VERSION 5.8 ;
BUSBITCHARS "[]" ;
DIVIDERCHAR "/" ;
UNITS
    DATABASE MICRONS 1000 ;
END UNITS

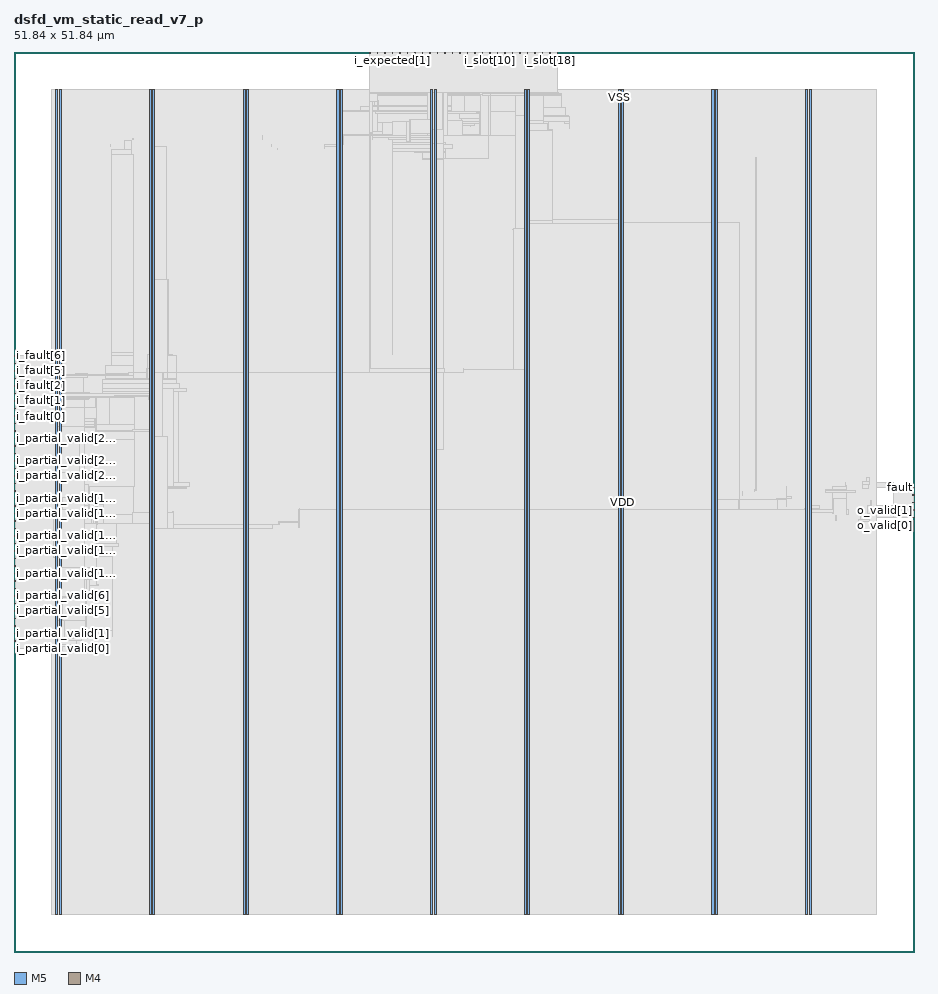
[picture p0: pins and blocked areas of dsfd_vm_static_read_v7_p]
MACRO dsfd_vm_static_read_v7_p
  FOREIGN dsfd_vm_static_read_v7_p 0 0 ;
  CLASS BLOCK ;
  SIZE 51.84 BY 51.84 ;
  PIN ck
    DIRECTION INPUT ;
    USE SIGNAL ;
    PORT
      LAYER M5 ;
        RECT  20.496 51.756 20.52 51.84 ;
    END
  END ck
  PIN fault
    DIRECTION OUTPUT ;
    USE SIGNAL ;
    PORT
      LAYER M4 ;
        RECT  51.756 26.736 51.84 26.76 ;
    END
  END fault
  PIN i_expected[0]
    DIRECTION INPUT ;
    USE SIGNAL ;
    PORT
      LAYER M5 ;
        RECT  21.36 51.756 21.384 51.84 ;
    END
  END i_expected[0]
  PIN i_expected[1]
    DIRECTION INPUT ;
    USE SIGNAL ;
    PORT
      LAYER M5 ;
        RECT  21.792 51.756 21.816 51.84 ;
    END
  END i_expected[1]
  PIN i_expected[2]
    DIRECTION INPUT ;
    USE SIGNAL ;
    PORT
      LAYER M5 ;
        RECT  22.224 51.756 22.248 51.84 ;
    END
  END i_expected[2]
  PIN i_expected[3]
    DIRECTION INPUT ;
    USE SIGNAL ;
    PORT
      LAYER M5 ;
        RECT  22.656 51.756 22.68 51.84 ;
    END
  END i_expected[3]
  PIN i_fault[0]
    DIRECTION INPUT ;
    USE SIGNAL ;
    PORT
      LAYER M4 ;
        RECT  0 31.296 0.084 31.32 ;
    END
  END i_fault[0]
  PIN i_fault[1]
    DIRECTION INPUT ;
    USE SIGNAL ;
    PORT
      LAYER M4 ;
        RECT  0 31.728 0.084 31.752 ;
    END
  END i_fault[1]
  PIN i_fault[2]
    DIRECTION INPUT ;
    USE SIGNAL ;
    PORT
      LAYER M4 ;
        RECT  0 32.16 0.084 32.184 ;
    END
  END i_fault[2]
  PIN i_fault[3]
    DIRECTION INPUT ;
    USE SIGNAL ;
    PORT
      LAYER M4 ;
        RECT  0 32.592 0.084 32.616 ;
    END
  END i_fault[3]
  PIN i_fault[4]
    DIRECTION INPUT ;
    USE SIGNAL ;
    PORT
      LAYER M4 ;
        RECT  0 33.024 0.084 33.048 ;
    END
  END i_fault[4]
  PIN i_fault[5]
    DIRECTION INPUT ;
    USE SIGNAL ;
    PORT
      LAYER M4 ;
        RECT  0 33.456 0.084 33.48 ;
    END
  END i_fault[5]
  PIN i_fault[6]
    DIRECTION INPUT ;
    USE SIGNAL ;
    PORT
      LAYER M4 ;
        RECT  0 33.888 0.084 33.912 ;
    END
  END i_fault[6]
  PIN i_fault[7]
    DIRECTION INPUT ;
    USE SIGNAL ;
    PORT
      LAYER M4 ;
        RECT  0 34.32 0.084 34.344 ;
    END
  END i_fault[7]
  PIN i_partial_valid[0]
    DIRECTION INPUT ;
    USE SIGNAL ;
    PORT
      LAYER M4 ;
        RECT  0 17.472 0.084 17.496 ;
    END
  END i_partial_valid[0]
  PIN i_partial_valid[10]
    DIRECTION INPUT ;
    USE SIGNAL ;
    PORT
      LAYER M4 ;
        RECT  0 21.792 0.084 21.816 ;
    END
  END i_partial_valid[10]
  PIN i_partial_valid[11]
    DIRECTION INPUT ;
    USE SIGNAL ;
    PORT
      LAYER M4 ;
        RECT  0 22.224 0.084 22.248 ;
    END
  END i_partial_valid[11]
  PIN i_partial_valid[12]
    DIRECTION INPUT ;
    USE SIGNAL ;
    PORT
      LAYER M4 ;
        RECT  0 22.656 0.084 22.68 ;
    END
  END i_partial_valid[12]
  PIN i_partial_valid[13]
    DIRECTION INPUT ;
    USE SIGNAL ;
    PORT
      LAYER M4 ;
        RECT  0 23.088 0.084 23.112 ;
    END
  END i_partial_valid[13]
  PIN i_partial_valid[14]
    DIRECTION INPUT ;
    USE SIGNAL ;
    PORT
      LAYER M4 ;
        RECT  0 23.52 0.084 23.544 ;
    END
  END i_partial_valid[14]
  PIN i_partial_valid[15]
    DIRECTION INPUT ;
    USE SIGNAL ;
    PORT
      LAYER M4 ;
        RECT  0 23.952 0.084 23.976 ;
    END
  END i_partial_valid[15]
  PIN i_partial_valid[16]
    DIRECTION INPUT ;
    USE SIGNAL ;
    PORT
      LAYER M4 ;
        RECT  0 24.384 0.084 24.408 ;
    END
  END i_partial_valid[16]
  PIN i_partial_valid[17]
    DIRECTION INPUT ;
    USE SIGNAL ;
    PORT
      LAYER M4 ;
        RECT  0 24.816 0.084 24.84 ;
    END
  END i_partial_valid[17]
  PIN i_partial_valid[18]
    DIRECTION INPUT ;
    USE SIGNAL ;
    PORT
      LAYER M4 ;
        RECT  0 25.248 0.084 25.272 ;
    END
  END i_partial_valid[18]
  PIN i_partial_valid[19]
    DIRECTION INPUT ;
    USE SIGNAL ;
    PORT
      LAYER M4 ;
        RECT  0 25.68 0.084 25.704 ;
    END
  END i_partial_valid[19]
  PIN i_partial_valid[1]
    DIRECTION INPUT ;
    USE SIGNAL ;
    PORT
      LAYER M4 ;
        RECT  0 17.904 0.084 17.928 ;
    END
  END i_partial_valid[1]
  PIN i_partial_valid[20]
    DIRECTION INPUT ;
    USE SIGNAL ;
    PORT
      LAYER M4 ;
        RECT  0 26.112 0.084 26.136 ;
    END
  END i_partial_valid[20]
  PIN i_partial_valid[21]
    DIRECTION INPUT ;
    USE SIGNAL ;
    PORT
      LAYER M4 ;
        RECT  0 26.544 0.084 26.568 ;
    END
  END i_partial_valid[21]
  PIN i_partial_valid[22]
    DIRECTION INPUT ;
    USE SIGNAL ;
    PORT
      LAYER M4 ;
        RECT  0 26.976 0.084 27 ;
    END
  END i_partial_valid[22]
  PIN i_partial_valid[23]
    DIRECTION INPUT ;
    USE SIGNAL ;
    PORT
      LAYER M4 ;
        RECT  0 27.408 0.084 27.432 ;
    END
  END i_partial_valid[23]
  PIN i_partial_valid[24]
    DIRECTION INPUT ;
    USE SIGNAL ;
    PORT
      LAYER M4 ;
        RECT  0 27.84 0.084 27.864 ;
    END
  END i_partial_valid[24]
  PIN i_partial_valid[25]
    DIRECTION INPUT ;
    USE SIGNAL ;
    PORT
      LAYER M4 ;
        RECT  0 28.272 0.084 28.296 ;
    END
  END i_partial_valid[25]
  PIN i_partial_valid[26]
    DIRECTION INPUT ;
    USE SIGNAL ;
    PORT
      LAYER M4 ;
        RECT  0 28.704 0.084 28.728 ;
    END
  END i_partial_valid[26]
  PIN i_partial_valid[27]
    DIRECTION INPUT ;
    USE SIGNAL ;
    PORT
      LAYER M4 ;
        RECT  0 29.136 0.084 29.16 ;
    END
  END i_partial_valid[27]
  PIN i_partial_valid[28]
    DIRECTION INPUT ;
    USE SIGNAL ;
    PORT
      LAYER M4 ;
        RECT  0 29.568 0.084 29.592 ;
    END
  END i_partial_valid[28]
  PIN i_partial_valid[29]
    DIRECTION INPUT ;
    USE SIGNAL ;
    PORT
      LAYER M4 ;
        RECT  0 30 0.084 30.024 ;
    END
  END i_partial_valid[29]
  PIN i_partial_valid[2]
    DIRECTION INPUT ;
    USE SIGNAL ;
    PORT
      LAYER M4 ;
        RECT  0 18.336 0.084 18.36 ;
    END
  END i_partial_valid[2]
  PIN i_partial_valid[30]
    DIRECTION INPUT ;
    USE SIGNAL ;
    PORT
      LAYER M4 ;
        RECT  0 30.432 0.084 30.456 ;
    END
  END i_partial_valid[30]
  PIN i_partial_valid[31]
    DIRECTION INPUT ;
    USE SIGNAL ;
    PORT
      LAYER M4 ;
        RECT  0 30.864 0.084 30.888 ;
    END
  END i_partial_valid[31]
  PIN i_partial_valid[3]
    DIRECTION INPUT ;
    USE SIGNAL ;
    PORT
      LAYER M4 ;
        RECT  0 18.768 0.084 18.792 ;
    END
  END i_partial_valid[3]
  PIN i_partial_valid[4]
    DIRECTION INPUT ;
    USE SIGNAL ;
    PORT
      LAYER M4 ;
        RECT  0 19.2 0.084 19.224 ;
    END
  END i_partial_valid[4]
  PIN i_partial_valid[5]
    DIRECTION INPUT ;
    USE SIGNAL ;
    PORT
      LAYER M4 ;
        RECT  0 19.632 0.084 19.656 ;
    END
  END i_partial_valid[5]
  PIN i_partial_valid[6]
    DIRECTION INPUT ;
    USE SIGNAL ;
    PORT
      LAYER M4 ;
        RECT  0 20.064 0.084 20.088 ;
    END
  END i_partial_valid[6]
  PIN i_partial_valid[7]
    DIRECTION INPUT ;
    USE SIGNAL ;
    PORT
      LAYER M4 ;
        RECT  0 20.496 0.084 20.52 ;
    END
  END i_partial_valid[7]
  PIN i_partial_valid[8]
    DIRECTION INPUT ;
    USE SIGNAL ;
    PORT
      LAYER M4 ;
        RECT  0 20.928 0.084 20.952 ;
    END
  END i_partial_valid[8]
  PIN i_partial_valid[9]
    DIRECTION INPUT ;
    USE SIGNAL ;
    PORT
      LAYER M4 ;
        RECT  0 21.36 0.084 21.384 ;
    END
  END i_partial_valid[9]
  PIN i_slot[0]
    DIRECTION INPUT ;
    USE SIGNAL ;
    PORT
      LAYER M5 ;
        RECT  23.088 51.756 23.112 51.84 ;
    END
  END i_slot[0]
  PIN i_slot[10]
    DIRECTION INPUT ;
    USE SIGNAL ;
    PORT
      LAYER M5 ;
        RECT  27.408 51.756 27.432 51.84 ;
    END
  END i_slot[10]
  PIN i_slot[11]
    DIRECTION INPUT ;
    USE SIGNAL ;
    PORT
      LAYER M5 ;
        RECT  27.84 51.756 27.864 51.84 ;
    END
  END i_slot[11]
  PIN i_slot[12]
    DIRECTION INPUT ;
    USE SIGNAL ;
    PORT
      LAYER M5 ;
        RECT  28.272 51.756 28.296 51.84 ;
    END
  END i_slot[12]
  PIN i_slot[13]
    DIRECTION INPUT ;
    USE SIGNAL ;
    PORT
      LAYER M5 ;
        RECT  28.704 51.756 28.728 51.84 ;
    END
  END i_slot[13]
  PIN i_slot[14]
    DIRECTION INPUT ;
    USE SIGNAL ;
    PORT
      LAYER M5 ;
        RECT  29.136 51.756 29.16 51.84 ;
    END
  END i_slot[14]
  PIN i_slot[15]
    DIRECTION INPUT ;
    USE SIGNAL ;
    PORT
      LAYER M5 ;
        RECT  29.568 51.756 29.592 51.84 ;
    END
  END i_slot[15]
  PIN i_slot[16]
    DIRECTION INPUT ;
    USE SIGNAL ;
    PORT
      LAYER M5 ;
        RECT  30 51.756 30.024 51.84 ;
    END
  END i_slot[16]
  PIN i_slot[17]
    DIRECTION INPUT ;
    USE SIGNAL ;
    PORT
      LAYER M5 ;
        RECT  30.432 51.756 30.456 51.84 ;
    END
  END i_slot[17]
  PIN i_slot[18]
    DIRECTION INPUT ;
    USE SIGNAL ;
    PORT
      LAYER M5 ;
        RECT  30.864 51.756 30.888 51.84 ;
    END
  END i_slot[18]
  PIN i_slot[19]
    DIRECTION INPUT ;
    USE SIGNAL ;
    PORT
      LAYER M5 ;
        RECT  31.296 51.756 31.32 51.84 ;
    END
  END i_slot[19]
  PIN i_slot[1]
    DIRECTION INPUT ;
    USE SIGNAL ;
    PORT
      LAYER M5 ;
        RECT  23.52 51.756 23.544 51.84 ;
    END
  END i_slot[1]
  PIN i_slot[2]
    DIRECTION INPUT ;
    USE SIGNAL ;
    PORT
      LAYER M5 ;
        RECT  23.952 51.756 23.976 51.84 ;
    END
  END i_slot[2]
  PIN i_slot[3]
    DIRECTION INPUT ;
    USE SIGNAL ;
    PORT
      LAYER M5 ;
        RECT  24.384 51.756 24.408 51.84 ;
    END
  END i_slot[3]
  PIN i_slot[4]
    DIRECTION INPUT ;
    USE SIGNAL ;
    PORT
      LAYER M5 ;
        RECT  24.816 51.756 24.84 51.84 ;
    END
  END i_slot[4]
  PIN i_slot[5]
    DIRECTION INPUT ;
    USE SIGNAL ;
    PORT
      LAYER M5 ;
        RECT  25.248 51.756 25.272 51.84 ;
    END
  END i_slot[5]
  PIN i_slot[6]
    DIRECTION INPUT ;
    USE SIGNAL ;
    PORT
      LAYER M5 ;
        RECT  25.68 51.756 25.704 51.84 ;
    END
  END i_slot[6]
  PIN i_slot[7]
    DIRECTION INPUT ;
    USE SIGNAL ;
    PORT
      LAYER M5 ;
        RECT  26.112 51.756 26.136 51.84 ;
    END
  END i_slot[7]
  PIN i_slot[8]
    DIRECTION INPUT ;
    USE SIGNAL ;
    PORT
      LAYER M5 ;
        RECT  26.544 51.756 26.568 51.84 ;
    END
  END i_slot[8]
  PIN i_slot[9]
    DIRECTION INPUT ;
    USE SIGNAL ;
    PORT
      LAYER M5 ;
        RECT  26.976 51.756 27 51.84 ;
    END
  END i_slot[9]
  PIN o_valid[0]
    DIRECTION OUTPUT ;
    USE SIGNAL ;
    PORT
      LAYER M4 ;
        RECT  51.756 25.008 51.84 25.032 ;
    END
  END o_valid[0]
  PIN o_valid[1]
    DIRECTION OUTPUT ;
    USE SIGNAL ;
    PORT
      LAYER M4 ;
        RECT  51.756 25.44 51.84 25.464 ;
    END
  END o_valid[1]
  PIN o_valid[2]
    DIRECTION OUTPUT ;
    USE SIGNAL ;
    PORT
      LAYER M4 ;
        RECT  51.756 25.872 51.84 25.896 ;
    END
  END o_valid[2]
  PIN o_valid[3]
    DIRECTION OUTPUT ;
    USE SIGNAL ;
    PORT
      LAYER M4 ;
        RECT  51.756 26.304 51.84 26.328 ;
    END
  END o_valid[3]
  PIN rst_n
    DIRECTION INPUT ;
    USE SIGNAL ;
    PORT
      LAYER M5 ;
        RECT  20.928 51.756 20.952 51.84 ;
    END
  END rst_n
  PIN VDD
    DIRECTION INOUT ;
    USE POWER ;
    PORT
      LAYER M5 ;
        RECT  45.792 2.151 45.912 49.689 ;
        RECT  40.392 2.151 40.512 49.689 ;
        RECT  34.992 2.151 35.112 49.689 ;
        RECT  29.592 2.151 29.712 49.689 ;
        RECT  24.192 2.151 24.312 49.689 ;
        RECT  18.792 2.151 18.912 49.689 ;
        RECT  13.392 2.151 13.512 49.689 ;
        RECT  7.992 2.151 8.112 49.689 ;
        RECT  2.592 2.151 2.712 49.689 ;
    END
  END VDD
  PIN VSS
    DIRECTION INOUT ;
    USE GROUND ;
    PORT
      LAYER M5 ;
        RECT  45.6 2.137 45.72 49.703 ;
        RECT  40.2 2.137 40.32 49.703 ;
        RECT  34.8 2.137 34.92 49.703 ;
        RECT  29.4 2.137 29.52 49.703 ;
        RECT  24 2.137 24.12 49.703 ;
        RECT  18.6 2.137 18.72 49.703 ;
        RECT  13.2 2.137 13.32 49.703 ;
        RECT  7.8 2.137 7.92 49.703 ;
        RECT  2.4 2.137 2.52 49.703 ;
    END
  END VSS
  # OT_OBS_CLOSED layer=M5 d_um=1.536 added=16
  OBS
    LAYER RVTN ;
     RECT  2.16 2.16 49.68 2.295 ;
     RECT  2.16 2.565 49.68 2.835 ;
     RECT  2.16 3.105 49.68 3.375 ;
     RECT  2.16 3.645 49.68 3.915 ;
     RECT  2.16 4.185 49.68 4.455 ;
     RECT  2.16 4.725 49.68 4.995 ;
     RECT  2.16 5.265 49.68 5.535 ;
     RECT  2.16 5.805 49.68 6.075 ;
     RECT  2.16 6.345 49.68 6.615 ;
     RECT  2.16 6.885 49.68 7.155 ;
     RECT  2.16 7.425 49.68 7.695 ;
     RECT  2.16 7.965 49.68 8.235 ;
     RECT  2.16 8.505 49.68 8.775 ;
     RECT  2.16 9.045 49.68 9.315 ;
     RECT  2.16 9.585 49.68 9.855 ;
     RECT  2.16 10.125 49.68 10.395 ;
     RECT  2.16 10.665 49.68 10.935 ;
     RECT  2.16 11.205 49.68 11.475 ;
     RECT  2.16 11.745 49.68 12.015 ;
     RECT  2.16 12.285 49.68 12.555 ;
     RECT  2.16 12.825 49.68 13.095 ;
     RECT  2.16 13.365 49.68 13.635 ;
     RECT  2.16 13.905 49.68 14.175 ;
     RECT  2.16 14.445 49.68 14.715 ;
     RECT  2.16 14.985 49.68 15.255 ;
     RECT  2.16 15.525 49.68 15.795 ;
     RECT  2.16 16.065 49.68 16.335 ;
     RECT  2.16 16.605 49.68 16.875 ;
     RECT  2.16 17.145 49.68 17.415 ;
     RECT  2.16 17.685 49.68 17.955 ;
     RECT  2.16 18.225 49.68 18.495 ;
     RECT  2.16 18.765 49.68 19.035 ;
     RECT  2.16 19.305 49.68 19.575 ;
     RECT  2.16 19.845 49.68 20.115 ;
     RECT  2.16 20.385 49.68 20.655 ;
     RECT  2.16 20.925 49.68 21.195 ;
     RECT  2.16 21.465 49.68 21.735 ;
     RECT  2.16 22.005 49.68 22.275 ;
     RECT  2.16 22.545 49.68 22.815 ;
     RECT  2.16 23.085 49.68 23.355 ;
     RECT  2.16 23.625 49.68 23.895 ;
     RECT  2.16 24.165 49.68 24.435 ;
     RECT  2.16 24.705 49.68 24.975 ;
     RECT  2.16 25.245 49.68 25.515 ;
     RECT  2.16 25.785 49.68 26.055 ;
     RECT  2.16 26.325 49.68 26.595 ;
     RECT  2.16 26.865 49.68 27.135 ;
     RECT  2.16 27.405 49.68 27.675 ;
     RECT  2.16 27.945 49.68 28.215 ;
     RECT  2.16 28.485 49.68 28.755 ;
     RECT  2.16 29.025 49.68 29.295 ;
     RECT  2.16 29.565 49.68 29.835 ;
     RECT  2.16 30.105 49.68 30.375 ;
     RECT  2.16 30.645 49.68 30.915 ;
     RECT  2.16 31.185 49.68 31.455 ;
     RECT  2.16 31.725 49.68 31.995 ;
     RECT  2.16 32.265 49.68 32.535 ;
     RECT  2.16 32.805 49.68 33.075 ;
     RECT  2.16 33.345 49.68 33.615 ;
     RECT  2.16 33.885 49.68 34.155 ;
     RECT  2.16 34.425 49.68 34.695 ;
     RECT  2.16 34.965 49.68 35.235 ;
     RECT  2.16 35.505 49.68 35.775 ;
     RECT  2.16 36.045 49.68 36.315 ;
     RECT  2.16 36.585 49.68 36.855 ;
     RECT  2.16 37.125 49.68 37.395 ;
     RECT  2.16 37.665 49.68 37.935 ;
     RECT  2.16 38.205 49.68 38.475 ;
     RECT  2.16 38.745 49.68 39.015 ;
     RECT  2.16 39.285 49.68 39.555 ;
     RECT  2.16 39.825 49.68 40.095 ;
     RECT  2.16 40.365 49.68 40.635 ;
     RECT  2.16 40.905 49.68 41.175 ;
     RECT  2.16 41.445 49.68 41.715 ;
     RECT  2.16 41.985 49.68 42.255 ;
     RECT  2.16 42.525 49.68 42.795 ;
     RECT  2.16 43.065 49.68 43.335 ;
     RECT  2.16 43.605 49.68 43.875 ;
     RECT  2.16 44.145 49.68 44.415 ;
     RECT  2.16 44.685 49.68 44.955 ;
     RECT  2.16 45.225 49.68 45.495 ;
     RECT  2.16 45.765 49.68 46.035 ;
     RECT  2.16 46.305 49.68 46.575 ;
     RECT  2.16 46.845 49.68 47.115 ;
     RECT  2.16 47.385 49.68 47.655 ;
     RECT  2.16 47.925 49.68 48.195 ;
     RECT  2.16 48.465 49.68 48.735 ;
     RECT  2.16 49.005 49.68 49.275 ;
     RECT  2.16 49.545 49.68 49.68 ;
    LAYER RVTP ;
     RECT  2.16 2.295 49.68 2.565 ;
     RECT  2.16 2.835 49.68 3.105 ;
     RECT  2.16 3.375 49.68 3.645 ;
     RECT  2.16 3.915 49.68 4.185 ;
     RECT  2.16 4.455 49.68 4.725 ;
     RECT  2.16 4.995 49.68 5.265 ;
     RECT  2.16 5.535 49.68 5.805 ;
     RECT  2.16 6.075 49.68 6.345 ;
     RECT  2.16 6.615 49.68 6.885 ;
     RECT  2.16 7.155 49.68 7.425 ;
     RECT  2.16 7.695 49.68 7.965 ;
     RECT  2.16 8.235 49.68 8.505 ;
     RECT  2.16 8.775 49.68 9.045 ;
     RECT  2.16 9.315 49.68 9.585 ;
     RECT  2.16 9.855 49.68 10.125 ;
     RECT  2.16 10.395 49.68 10.665 ;
     RECT  2.16 10.935 49.68 11.205 ;
     RECT  2.16 11.475 49.68 11.745 ;
     RECT  2.16 12.015 49.68 12.285 ;
     RECT  2.16 12.555 49.68 12.825 ;
     RECT  2.16 13.095 49.68 13.365 ;
     RECT  2.16 13.635 49.68 13.905 ;
     RECT  2.16 14.175 49.68 14.445 ;
     RECT  2.16 14.715 49.68 14.985 ;
     RECT  2.16 15.255 49.68 15.525 ;
     RECT  2.16 15.795 49.68 16.065 ;
     RECT  2.16 16.335 49.68 16.605 ;
     RECT  2.16 16.875 49.68 17.145 ;
     RECT  2.16 17.415 49.68 17.685 ;
     RECT  2.16 17.955 49.68 18.225 ;
     RECT  2.16 18.495 49.68 18.765 ;
     RECT  2.16 19.035 49.68 19.305 ;
     RECT  2.16 19.575 49.68 19.845 ;
     RECT  2.16 20.115 49.68 20.385 ;
     RECT  2.16 20.655 49.68 20.925 ;
     RECT  2.16 21.195 49.68 21.465 ;
     RECT  2.16 21.735 49.68 22.005 ;
     RECT  2.16 22.275 49.68 22.545 ;
     RECT  2.16 22.815 49.68 23.085 ;
     RECT  2.16 23.355 49.68 23.625 ;
     RECT  2.16 23.895 49.68 24.165 ;
     RECT  2.16 24.435 49.68 24.705 ;
     RECT  2.16 24.975 49.68 25.245 ;
     RECT  2.16 25.515 49.68 25.785 ;
     RECT  2.16 26.055 49.68 26.325 ;
     RECT  2.16 26.595 49.68 26.865 ;
     RECT  2.16 27.135 49.68 27.405 ;
     RECT  2.16 27.675 49.68 27.945 ;
     RECT  2.16 28.215 49.68 28.485 ;
     RECT  2.16 28.755 49.68 29.025 ;
     RECT  2.16 29.295 49.68 29.565 ;
     RECT  2.16 29.835 49.68 30.105 ;
     RECT  2.16 30.375 49.68 30.645 ;
     RECT  2.16 30.915 49.68 31.185 ;
     RECT  2.16 31.455 49.68 31.725 ;
     RECT  2.16 31.995 49.68 32.265 ;
     RECT  2.16 32.535 49.68 32.805 ;
     RECT  2.16 33.075 49.68 33.345 ;
     RECT  2.16 33.615 49.68 33.885 ;
     RECT  2.16 34.155 49.68 34.425 ;
     RECT  2.16 34.695 49.68 34.965 ;
     RECT  2.16 35.235 49.68 35.505 ;
     RECT  2.16 35.775 49.68 36.045 ;
     RECT  2.16 36.315 49.68 36.585 ;
     RECT  2.16 36.855 49.68 37.125 ;
     RECT  2.16 37.395 49.68 37.665 ;
     RECT  2.16 37.935 49.68 38.205 ;
     RECT  2.16 38.475 49.68 38.745 ;
     RECT  2.16 39.015 49.68 39.285 ;
     RECT  2.16 39.555 49.68 39.825 ;
     RECT  2.16 40.095 49.68 40.365 ;
     RECT  2.16 40.635 49.68 40.905 ;
     RECT  2.16 41.175 49.68 41.445 ;
     RECT  2.16 41.715 49.68 41.985 ;
     RECT  2.16 42.255 49.68 42.525 ;
     RECT  2.16 42.795 49.68 43.065 ;
     RECT  2.16 43.335 49.68 43.605 ;
     RECT  2.16 43.875 49.68 44.145 ;
     RECT  2.16 44.415 49.68 44.685 ;
     RECT  2.16 44.955 49.68 45.225 ;
     RECT  2.16 45.495 49.68 45.765 ;
     RECT  2.16 46.035 49.68 46.305 ;
     RECT  2.16 46.575 49.68 46.845 ;
     RECT  2.16 47.115 49.68 47.385 ;
     RECT  2.16 47.655 49.68 47.925 ;
     RECT  2.16 48.195 49.68 48.465 ;
     RECT  2.16 48.735 49.68 49.005 ;
     RECT  2.16 49.275 49.68 49.545 ;
    LAYER M1 ;
     RECT  2.16 2.151 49.68 49.689 ;
    LAYER M2 ;
     RECT  0.103 17.46 2.16 18.216 ;
     RECT  0.535 23.706 2.16 23.724 ;
     RECT  2.16 2.151 49.68 49.689 ;
     RECT  49.68 26.766 50.207 27.054 ;
     RECT  50.207 27.036 50.675 27.054 ;
     RECT  49.68 25.02 50.711 25.704 ;
     RECT  50.711 25.326 50.747 25.344 ;
    LAYER M3 ;
     RECT  2.415 2.143 2.505 2.413 ;
     RECT  7.815 2.143 7.905 2.413 ;
     RECT  13.215 2.143 13.305 2.413 ;
     RECT  18.615 2.143 18.705 2.413 ;
     RECT  24.015 2.143 24.105 2.413 ;
     RECT  29.415 2.143 29.505 2.413 ;
     RECT  34.815 2.143 34.905 2.413 ;
     RECT  40.215 2.143 40.305 2.413 ;
     RECT  45.615 2.143 45.705 2.413 ;
     RECT  2.415 2.413 2.697 17.185 ;
     RECT  2.376 17.185 2.697 17.311 ;
     RECT  2.34 17.311 2.697 17.383 ;
     RECT  2.34 17.383 2.79 17.467 ;
     RECT  2.304 17.467 2.79 17.581 ;
     RECT  2.304 17.581 3.042 17.725 ;
     RECT  2.304 17.725 3.618 17.959 ;
     RECT  2.304 17.959 3.87 18.031 ;
     RECT  2.304 18.031 4.338 18.187 ;
     RECT  2.304 18.187 4.41 18.535 ;
     RECT  5.652 18.193 5.67 18.535 ;
     RECT  0.108 17.455 0.126 18.797 ;
     RECT  2.304 18.535 5.67 22.775 ;
     RECT  2.34 22.775 5.67 23.359 ;
     RECT  2.34 23.359 6.03 23.515 ;
     RECT  2.304 23.515 6.03 23.549 ;
     RECT  0.54 23.701 0.558 23.981 ;
     RECT  14.832 24.367 14.85 24.413 ;
     RECT  16.38 24.469 16.398 24.509 ;
     RECT  48.636 24.745 48.654 24.781 ;
     RECT  15.264 24.619 15.282 24.809 ;
     RECT  48.636 24.781 49.266 24.899 ;
     RECT  2.304 23.549 5.922 25.015 ;
     RECT  2.304 25.015 6.354 25.147 ;
     RECT  47.34 24.871 47.358 25.169 ;
     RECT  48.78 24.899 49.266 25.169 ;
     RECT  8.82 25.195 8.838 25.241 ;
     RECT  49.176 25.169 49.266 25.285 ;
     RECT  45.615 2.413 45.897 25.321 ;
     RECT  47.16 25.249 47.178 25.321 ;
     RECT  50.688 25.003 50.706 25.321 ;
     RECT  9.144 25.291 9.162 25.349 ;
     RECT  47.952 25.177 48.042 25.475 ;
     RECT  45.615 25.321 47.178 25.477 ;
     RECT  45.54 25.477 47.178 25.511 ;
     RECT  45.54 25.511 46.422 25.517 ;
     RECT  42.768 25.519 42.786 25.619 ;
     RECT  45.612 25.517 46.422 25.709 ;
     RECT  49.176 25.285 49.374 25.745 ;
     RECT  50.688 25.321 50.742 25.901 ;
     RECT  49.356 25.745 49.374 25.979 ;
     RECT  44.496 25.681 44.514 26.059 ;
     RECT  43.92 26.059 44.514 26.095 ;
     RECT  43.92 26.095 44.802 26.096 ;
     RECT  47.16 25.511 47.178 26.131 ;
     RECT  47.952 25.475 47.97 26.131 ;
     RECT  44.496 26.096 44.802 26.249 ;
     RECT  45.612 25.709 45.897 26.285 ;
     RECT  47.16 26.131 47.97 26.491 ;
     RECT  41.94 26.293 41.958 26.519 ;
     RECT  46.728 26.491 48.474 26.591 ;
     RECT  42.66 26.527 42.678 26.599 ;
     RECT  46.728 26.591 47.97 26.627 ;
     RECT  42.66 26.599 42.75 26.663 ;
     RECT  41.76 26.629 41.778 26.669 ;
     RECT  8.82 26.401 8.838 26.671 ;
     RECT  50.652 26.299 50.67 26.731 ;
     RECT  7.815 2.413 8.097 26.779 ;
     RECT  8.82 26.671 9.954 26.779 ;
     RECT  44.496 26.249 44.514 26.789 ;
     RECT  47.16 26.627 47.97 26.789 ;
     RECT  50.184 26.731 50.67 26.789 ;
     RECT  2.304 25.147 6.858 26.797 ;
     RECT  7.815 26.779 9.954 26.797 ;
     RECT  42.732 26.663 42.75 26.797 ;
     RECT  7.815 26.797 10.134 26.825 ;
     RECT  47.88 26.789 47.97 26.861 ;
     RECT  48.888 26.671 49.194 26.905 ;
     RECT  9.216 26.825 10.134 27.059 ;
     RECT  42.732 26.797 42.786 27.059 ;
     RECT  47.88 26.861 47.898 27.059 ;
     RECT  50.652 26.789 50.67 27.059 ;
     RECT  48.888 26.905 49.302 27.095 ;
     RECT  49.104 27.095 49.302 27.329 ;
     RECT  24.015 2.413 24.297 28.921 ;
     RECT  0.108 29.131 0.126 29.261 ;
     RECT  2.304 26.797 6.93 29.525 ;
     RECT  0.108 29.995 0.126 30.125 ;
     RECT  2.34 29.525 6.93 30.371 ;
     RECT  2.34 30.371 4.734 30.569 ;
     RECT  4.716 30.569 4.734 30.749 ;
     RECT  2.34 30.569 3.906 30.955 ;
     RECT  2.304 30.955 3.906 31.325 ;
     RECT  2.34 31.325 3.906 31.339 ;
     RECT  2.34 31.339 4.086 31.801 ;
     RECT  7.815 26.825 8.097 31.801 ;
     RECT  2.34 31.801 4.302 31.891 ;
     RECT  2.34 31.891 4.374 31.915 ;
     RECT  5.472 30.371 6.93 31.915 ;
     RECT  2.34 31.915 6.93 31.999 ;
     RECT  7.74 31.801 8.097 31.999 ;
     RECT  2.34 31.999 8.097 32.155 ;
     RECT  2.304 32.155 8.097 32.189 ;
     RECT  2.304 32.189 4.374 32.225 ;
     RECT  5.112 32.189 8.097 32.305 ;
     RECT  9.216 27.059 9.45 32.305 ;
     RECT  5.112 32.305 8.19 32.431 ;
     RECT  9.216 32.305 9.918 32.431 ;
     RECT  5.112 32.431 9.918 32.459 ;
     RECT  5.112 32.459 9.522 32.729 ;
     RECT  5.112 32.729 9.378 32.999 ;
     RECT  5.292 32.999 9.378 33.053 ;
     RECT  2.304 32.225 4.014 33.079 ;
     RECT  2.304 33.079 4.23 33.245 ;
     RECT  3.564 33.245 4.23 33.341 ;
     RECT  5.292 33.053 8.097 33.341 ;
     RECT  24.015 28.921 24.714 33.511 ;
     RECT  2.304 33.245 2.754 33.575 ;
     RECT  25.884 33.355 25.902 33.598 ;
     RECT  7.632 33.341 8.097 33.629 ;
     RECT  24.015 33.511 24.786 33.629 ;
     RECT  5.292 33.341 6.858 33.809 ;
     RECT  2.415 33.575 2.754 33.953 ;
     RECT  2.415 33.953 2.697 34.315 ;
     RECT  8.856 33.053 9.378 34.349 ;
     RECT  5.616 33.809 6.858 34.357 ;
     RECT  2.304 34.315 2.697 34.385 ;
     RECT  8.856 34.349 9.126 34.421 ;
     RECT  5.616 34.357 6.894 34.529 ;
     RECT  8.856 34.421 8.91 34.655 ;
     RECT  7.815 33.629 8.097 38.713 ;
     RECT  8.856 34.655 8.874 38.713 ;
     RECT  7.815 38.713 8.874 38.741 ;
     RECT  33.948 41.947 33.966 41.995 ;
     RECT  34.815 2.413 35.097 41.995 ;
     RECT  33.948 41.995 35.097 42.179 ;
     RECT  24.015 33.629 24.714 45.661 ;
     RECT  23.544 45.661 24.714 45.733 ;
     RECT  42.732 27.059 42.75 45.761 ;
     RECT  5.616 34.529 6.858 45.959 ;
     RECT  23.544 45.733 24.858 46.039 ;
     RECT  23.112 46.039 24.858 46.075 ;
     RECT  21.78 34.393 21.798 46.111 ;
     RECT  23.076 46.075 24.858 46.111 ;
     RECT  5.616 45.959 6.786 46.229 ;
     RECT  15.156 46.201 15.174 46.265 ;
     RECT  21.78 46.111 24.858 46.309 ;
     RECT  17.856 46.273 17.874 46.381 ;
     RECT  18.615 2.413 18.897 46.381 ;
     RECT  7.815 38.741 8.802 46.409 ;
     RECT  5.544 46.381 5.562 46.499 ;
     RECT  14.832 46.381 14.85 46.499 ;
     RECT  17.856 46.381 18.897 46.499 ;
     RECT  21.78 46.309 25.254 46.499 ;
     RECT  18.615 46.499 18.897 46.507 ;
     RECT  21.78 46.499 24.858 46.607 ;
     RECT  6.336 46.229 6.786 46.769 ;
     RECT  21.78 46.607 24.714 46.777 ;
     RECT  6.84 46.777 6.858 46.877 ;
     RECT  20.628 46.813 20.646 46.921 ;
     RECT  21.564 46.777 24.714 46.921 ;
     RECT  18.615 46.507 18.954 47.035 ;
     RECT  29.415 2.413 29.697 47.035 ;
     RECT  14.292 46.777 14.31 47.039 ;
     RECT  18.615 47.035 19.53 47.075 ;
     RECT  20.628 46.921 24.714 47.075 ;
     RECT  20.628 47.075 21.222 47.261 ;
     RECT  22.104 47.075 24.714 47.461 ;
     RECT  26.28 47.551 26.298 47.587 ;
     RECT  30.78 47.323 30.798 47.707 ;
     RECT  25.776 47.587 26.55 47.731 ;
     RECT  27.324 47.587 27.342 47.731 ;
     RECT  28.836 47.035 29.697 47.731 ;
     RECT  30.528 47.707 30.798 47.731 ;
     RECT  31.968 47.425 31.986 47.731 ;
     RECT  20.952 47.261 21.222 47.803 ;
     RECT  22.104 47.461 24.858 47.803 ;
     RECT  25.776 47.731 30.798 47.821 ;
     RECT  31.68 47.731 31.986 47.821 ;
     RECT  25.776 47.821 31.986 47.849 ;
     RECT  25.776 47.849 29.697 48.001 ;
     RECT  30.492 47.849 31.986 48.119 ;
     RECT  30.492 48.119 31.95 48.191 ;
     RECT  20.952 47.803 24.858 48.271 ;
     RECT  25.668 48.001 29.697 48.271 ;
     RECT  20.808 48.271 29.697 48.389 ;
     RECT  20.808 48.389 25.182 48.397 ;
     RECT  20.556 48.397 25.182 48.427 ;
     RECT  19.836 48.427 25.182 48.467 ;
     RECT  30.492 48.191 31.77 48.659 ;
     RECT  19.98 48.467 25.182 48.695 ;
     RECT  20.7 48.695 25.182 48.731 ;
     RECT  20.772 48.731 25.182 49.351 ;
     RECT  25.956 48.389 29.697 49.351 ;
     RECT  30.492 48.659 31.554 49.351 ;
     RECT  20.772 49.351 31.554 49.373 ;
     RECT  2.415 34.385 2.697 49.427 ;
     RECT  7.815 46.409 8.097 49.427 ;
     RECT  13.215 2.413 13.497 49.427 ;
     RECT  18.615 47.075 18.897 49.427 ;
     RECT  34.815 42.179 35.097 49.427 ;
     RECT  40.215 2.413 40.497 49.427 ;
     RECT  45.615 26.285 45.897 49.427 ;
     RECT  20.772 49.373 26.838 49.469 ;
     RECT  27.612 49.373 31.554 49.469 ;
     RECT  20.772 49.469 26.334 49.505 ;
     RECT  21.024 49.505 26.334 49.517 ;
     RECT  27.612 49.469 31.338 49.517 ;
     RECT  21.024 49.517 21.33 49.541 ;
     RECT  21.312 49.541 21.33 49.565 ;
     RECT  28.692 49.517 30.834 49.565 ;
     RECT  22.104 49.517 26.334 49.577 ;
     RECT  27.612 49.517 27.63 49.577 ;
     RECT  28.692 49.565 30.438 49.577 ;
     RECT  2.415 49.427 2.505 49.697 ;
     RECT  7.815 49.427 7.905 49.697 ;
     RECT  13.215 49.427 13.305 49.697 ;
     RECT  18.615 49.427 18.705 49.697 ;
     RECT  23.832 49.577 24.105 49.697 ;
     RECT  29.415 49.577 29.574 49.697 ;
     RECT  34.815 49.427 34.905 49.697 ;
     RECT  40.215 49.427 40.305 49.697 ;
     RECT  45.615 49.427 45.705 49.697 ;
     RECT  29.556 49.697 29.574 49.805 ;
     RECT  22.104 49.577 22.122 50.765 ;
     RECT  23.832 49.697 23.85 50.765 ;
    LAYER M4 ;
     RECT  0.06 17.472 2.408 34.344 ;
     RECT  2.408 2.148 2.512 49.692 ;
     RECT  2.512 2.418 2.704 49.422 ;
     RECT  2.704 33.216 2.765 33.912 ;
     RECT  2.704 18.048 2.801 31.752 ;
     RECT  2.801 18.048 2.873 30.792 ;
     RECT  2.873 23.952 2.945 30.792 ;
     RECT  2.945 23.952 2.981 30.6 ;
     RECT  2.873 18.048 3.449 22.824 ;
     RECT  3.449 18.048 3.557 22.632 ;
     RECT  2.981 23.952 3.58 30.264 ;
     RECT  3.557 18.192 3.629 22.632 ;
     RECT  3.58 28.464 3.635 30.264 ;
     RECT  3.635 28.464 3.827 29.064 ;
     RECT  3.827 28.464 3.868 28.488 ;
     RECT  3.58 23.952 4.057 26.952 ;
     RECT  3.629 18.192 4.061 22.488 ;
     RECT  4.013 31.344 4.097 31.368 ;
     RECT  4.061 18.192 4.163 18.552 ;
     RECT  4.061 20.304 4.169 22.488 ;
     RECT  4.057 23.856 4.277 26.952 ;
     RECT  4.169 20.304 4.349 22.2 ;
     RECT  4.277 23.856 4.349 26.76 ;
     RECT  4.163 18.192 4.421 18.216 ;
     RECT  4.349 23.856 4.565 25.896 ;
     RECT  3.635 30.24 4.661 30.264 ;
     RECT  4.661 30.24 4.669 30.744 ;
     RECT  4.565 23.856 4.693 25.8 ;
     RECT  4.349 21.12 4.739 21.672 ;
     RECT  4.693 23.52 4.739 25.8 ;
     RECT  4.669 30 4.745 30.744 ;
     RECT  4.739 23.52 4.78 23.544 ;
     RECT  4.739 24.624 4.817 25.8 ;
     RECT  4.693 31.92 4.853 31.944 ;
     RECT  4.739 21.12 4.889 21.144 ;
     RECT  4.817 24.672 5.177 25.8 ;
     RECT  2.765 33.216 6.613 33.24 ;
     RECT  5.177 24.672 6.829 25.176 ;
     RECT  4.745 30 6.829 30.024 ;
     RECT  6.613 33.216 6.865 33.384 ;
     RECT  6.865 33.024 7.621 33.384 ;
     RECT  7.621 33.024 7.669 33.624 ;
     RECT  6.829 24.672 7.808 25.32 ;
     RECT  6.829 30 7.808 30.12 ;
     RECT  5.785 32.016 7.808 32.04 ;
     RECT  7.669 33.024 7.808 34.392 ;
     RECT  7.808 2.148 7.912 49.692 ;
     RECT  7.912 2.418 8.104 49.422 ;
     RECT  8.104 29.664 8.579 30.12 ;
     RECT  8.104 33.024 8.633 33.384 ;
     RECT  8.104 26.784 8.705 26.808 ;
     RECT  8.579 29.664 8.867 29.688 ;
     RECT  8.104 24.384 9.173 25.32 ;
     RECT  9.173 24.384 13.208 24.648 ;
     RECT  8.633 33.36 13.208 33.384 ;
     RECT  13.208 2.148 13.312 49.692 ;
     RECT  13.312 2.418 13.504 49.422 ;
     RECT  13.504 24.384 14.861 24.648 ;
     RECT  14.861 24.624 15.253 24.648 ;
     RECT  15.253 24.624 15.293 24.792 ;
     RECT  15.293 24.768 16.364 24.792 ;
     RECT  16.364 24.48 16.405 24.792 ;
     RECT  16.405 24.48 16.451 25.512 ;
     RECT  16.451 25.488 18.608 25.512 ;
     RECT  13.504 33.36 18.608 33.384 ;
     RECT  18.608 2.148 18.712 49.692 ;
     RECT  18.712 2.418 18.904 49.422 ;
     RECT  18.904 33.36 20.485 33.384 ;
     RECT  18.904 47.04 20.588 47.064 ;
     RECT  20.588 47.04 20.675 47.256 ;
     RECT  18.904 48.432 20.917 48.456 ;
     RECT  20.917 48.432 21.017 49.032 ;
     RECT  21.301 49.488 21.395 49.56 ;
     RECT  21.017 48.432 21.593 48.456 ;
     RECT  20.675 47.04 21.805 47.064 ;
     RECT  21.395 49.488 21.881 49.512 ;
     RECT  22.093 50.736 22.259 50.76 ;
     RECT  21.805 47.04 22.597 47.832 ;
     RECT  22.597 46.704 22.789 47.832 ;
     RECT  22.789 46.704 22.817 47.928 ;
     RECT  22.817 47.04 23.821 47.928 ;
     RECT  22.525 49.536 23.821 49.56 ;
     RECT  23.533 45.696 23.965 45.72 ;
     RECT  23.821 47.04 23.965 49.56 ;
     RECT  23.821 50.736 23.987 50.76 ;
     RECT  18.904 25.488 24.008 25.512 ;
     RECT  20.485 33.36 24.008 33.624 ;
     RECT  23.965 45.696 24.008 49.56 ;
     RECT  24.008 2.148 24.112 49.692 ;
     RECT  24.112 2.418 24.304 49.56 ;
     RECT  24.304 45.696 24.755 49.56 ;
     RECT  24.304 33.36 24.797 33.624 ;
     RECT  24.755 47.04 24.941 49.56 ;
     RECT  24.941 47.04 25.805 47.88 ;
     RECT  24.797 33.36 25.873 33.384 ;
     RECT  25.873 33.36 25.913 33.576 ;
     RECT  24.941 49.536 26.579 49.56 ;
     RECT  25.805 47.04 26.809 47.064 ;
     RECT  26.665 48.384 26.809 48.408 ;
     RECT  26.809 47.04 26.845 48.408 ;
     RECT  24.755 45.696 27.347 45.72 ;
     RECT  26.845 47.04 27.443 49.368 ;
     RECT  27.601 49.488 28.361 49.56 ;
     RECT  28.741 41.616 28.885 41.64 ;
     RECT  24.304 25.488 29.408 25.512 ;
     RECT  25.913 33.552 29.408 33.576 ;
     RECT  28.885 41.616 29.408 41.976 ;
     RECT  27.443 47.04 29.408 48.408 ;
     RECT  28.361 49.536 29.408 49.56 ;
     RECT  29.408 2.148 29.512 49.692 ;
     RECT  29.512 2.418 29.516 49.692 ;
     RECT  29.516 2.418 29.603 49.8 ;
     RECT  29.603 2.418 29.704 49.56 ;
     RECT  29.704 47.712 30.521 47.88 ;
     RECT  30.521 47.712 30.709 47.736 ;
     RECT  30.709 47.328 30.755 47.736 ;
     RECT  29.704 49.536 30.899 49.56 ;
     RECT  29.704 41.952 30.997 41.976 ;
     RECT  30.755 47.328 31.043 47.352 ;
     RECT  31.285 49.488 31.372 49.512 ;
     RECT  29.704 25.488 34.808 25.512 ;
     RECT  30.997 41.952 34.808 42.168 ;
     RECT  34.808 2.148 34.912 49.692 ;
     RECT  34.912 2.418 35.104 49.422 ;
     RECT  35.104 25.488 40.208 25.512 ;
     RECT  35.104 42 40.208 42.024 ;
     RECT  40.208 2.148 40.312 49.692 ;
     RECT  40.312 2.418 40.504 49.422 ;
     RECT  40.504 25.488 41.749 25.512 ;
     RECT  41.708 26.64 41.749 26.664 ;
     RECT  41.749 25.488 41.795 26.664 ;
     RECT  40.504 42 41.795 42.024 ;
     RECT  41.795 25.488 43.949 26.088 ;
     RECT  43.949 25.488 45.608 25.512 ;
     RECT  45.608 2.148 45.712 49.692 ;
     RECT  45.712 2.418 45.904 49.422 ;
     RECT  45.904 25.488 47.189 25.512 ;
     RECT  50.173 26.736 50.641 26.76 ;
     RECT  50.641 26.304 50.677 26.76 ;
     RECT  50.677 25.008 51.804 26.76 ;
    LAYER M5 ;
     RECT  2.4 2.137 2.52 2.151 ;
     RECT  7.8 2.137 7.92 2.151 ;
     RECT  13.2 2.137 13.32 2.151 ;
     RECT  18.6 2.137 18.72 2.151 ;
     RECT  24 2.137 24.12 2.151 ;
     RECT  29.4 2.137 29.52 2.151 ;
     RECT  34.8 2.137 34.92 2.151 ;
     RECT  40.2 2.137 40.32 2.151 ;
     RECT  45.6 2.137 45.72 2.151 ;
     RECT  2.4 2.151 2.712 18.037 ;
     RECT  2.4 18.037 2.904 19.091 ;
     RECT  2.4 19.091 2.808 20.435 ;
     RECT  4.128 18.517 4.152 20.485 ;
     RECT  4.08 20.485 4.152 21.445 ;
     RECT  4.08 21.445 4.44 21.637 ;
     RECT  4.08 21.637 4.728 22.165 ;
     RECT  2.4 20.435 2.712 22.741 ;
     RECT  7.8 2.151 8.112 24.373 ;
     RECT  4.032 22.165 4.728 24.659 ;
     RECT  4.032 24.659 4.44 24.947 ;
     RECT  2.304 22.741 2.712 25.235 ;
     RECT  4.032 24.947 4.392 25.331 ;
     RECT  2.4 25.235 2.712 25.477 ;
     RECT  16.416 24.469 16.44 25.523 ;
     RECT  4.032 25.331 4.296 25.715 ;
     RECT  2.4 25.477 2.808 26.197 ;
     RECT  4.032 25.715 4.056 26.197 ;
     RECT  2.4 26.197 4.056 27.635 ;
     RECT  2.4 27.635 2.712 29.365 ;
     RECT  3.792 27.635 4.056 29.365 ;
     RECT  7.8 24.373 8.856 29.699 ;
     RECT  2.4 29.365 4.056 30.275 ;
     RECT  4.032 30.275 4.056 30.709 ;
     RECT  4.032 30.709 4.728 31.379 ;
     RECT  4.704 31.379 4.728 31.955 ;
     RECT  7.8 29.699 8.568 33.395 ;
     RECT  29.4 2.151 29.712 33.541 ;
     RECT  7.8 33.395 8.112 33.589 ;
     RECT  7.68 33.589 8.112 34.403 ;
     RECT  28.752 33.541 29.712 41.651 ;
     RECT  41.76 26.053 41.784 42.035 ;
     RECT  24 2.151 24.312 46.597 ;
     RECT  20.496 33.589 20.52 47.221 ;
     RECT  31.008 42.133 31.032 47.317 ;
     RECT  24 46.597 24.744 47.363 ;
     RECT  30.72 47.317 31.032 47.363 ;
     RECT  30.72 47.363 30.744 47.747 ;
     RECT  22.8 47.173 22.824 47.939 ;
     RECT  27.312 45.685 27.336 48.083 ;
     RECT  28.896 41.651 29.712 48.179 ;
     RECT  20.496 47.221 20.664 48.997 ;
     RECT  20.496 48.997 20.952 49.477 ;
     RECT  26.976 49.333 27.432 49.477 ;
     RECT  20.496 49.477 21.816 49.525 ;
     RECT  24 47.363 24.696 49.525 ;
     RECT  26.976 49.477 28.296 49.525 ;
     RECT  29.4 48.179 29.712 49.525 ;
     RECT  31.296 49.477 31.32 49.525 ;
     RECT  2.4 30.275 2.712 49.689 ;
     RECT  7.8 34.403 8.112 49.689 ;
     RECT  13.2 2.151 13.512 49.689 ;
     RECT  18.6 2.151 18.912 49.689 ;
     RECT  34.8 2.151 35.112 49.689 ;
     RECT  40.2 2.151 40.512 49.689 ;
     RECT  45.6 2.151 45.912 49.689 ;
     RECT  2.4 49.689 2.52 49.703 ;
     RECT  7.8 49.689 7.92 49.703 ;
     RECT  13.2 49.689 13.32 49.703 ;
     RECT  18.6 49.689 18.72 49.703 ;
     RECT  34.8 49.689 34.92 49.703 ;
     RECT  40.2 49.689 40.32 49.703 ;
     RECT  45.6 49.689 45.72 49.703 ;
     RECT  20.496 49.525 31.32 51.792 ;
     RECT  2.904 18.517 4.128 19.091 ;
     RECT  2.808 19.091 4.128 20.435 ;
     RECT  2.712 20.435 4.128 20.485 ;
     RECT  2.712 20.485 4.08 22.165 ;
     RECT  2.712 22.165 4.032 25.477 ;
     RECT  2.808 25.477 4.032 26.197 ;
     RECT  40.512 26.053 41.76 42.035 ;
     RECT  2.712 27.635 3.792 29.365 ;
     RECT  2.712 30.275 4.032 31.379 ;
     RECT  29.712 42.133 31.008 47.317 ;
     RECT  22.824 47.173 24 47.939 ;
     RECT  29.712 47.317 30.72 47.747 ;
     RECT  27.312 48.083 27.336 49.333 ;
     RECT  28.896 48.179 29.4 49.333 ;
     RECT  27.432 49.333 29.4 49.477 ;
     RECT  28.296 49.477 29.4 49.525 ;
  END
END dsfd_vm_static_read_v7_p
END LIBRARY
